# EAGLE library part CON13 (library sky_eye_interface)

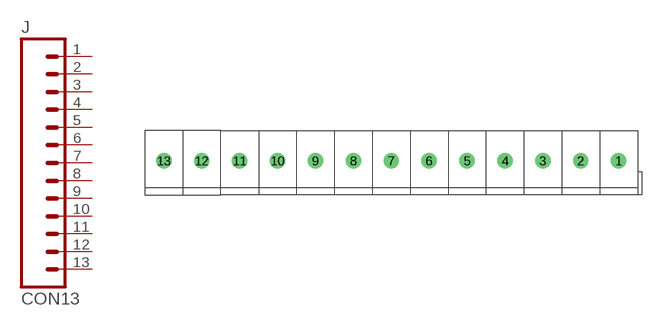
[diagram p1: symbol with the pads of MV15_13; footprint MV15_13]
Designator prefix J

## CON13  [MV15_13]
1  13  pas
2  12  pas
3  11  pas
4  10  pas
5  9  pas
6  8  pas
7  7  pas
8  6  pas
9  5  pas
10  4  pas
11  3  pas
12  2  pas
13  1  pas

## Footprint MV15_13 (pad centres in mm)
drill 1.016 pad 2.032 round: 1 62.5,0.25; 2 57.5,0.25; 3 52.5,0.25; 4 47.5,0.25; 5 42.5,0.25; 6 37.5,0.25; 7 32.5,0.25; 8 27.5,0.25; 9 22.5,0.25; 10 17.5,0.25; 11 12.5,0.25; 12 7.5,0.25; 13 2.5,0.25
